VERSION 5.7 ;
  NOWIREEXTENSIONATPIN ON ;
  DIVIDERCHAR "/" ;
  BUSBITCHARS "[]" ;
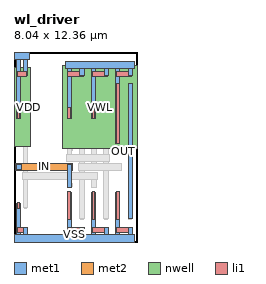
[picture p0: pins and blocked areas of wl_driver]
MACRO wl_driver
  CLASS BLOCK ;
  FOREIGN wl_driver ;
  ORIGIN 0.030 0.000 ;
  SIZE 8.040 BY 12.360 ;
  PIN IN
    DIRECTION INPUT ;
    USE SIGNAL ;
    ANTENNAGATEAREA 1.225000 ;
    PORT
      LAYER met1 ;
        RECT 0.140 4.720 0.430 5.040 ;
        RECT 3.440 3.560 3.730 5.040 ;
      LAYER met2 ;
        RECT 0.080 4.660 3.790 5.100 ;
    END
  END IN
  PIN OUT
    DIRECTION OUTPUT ;
    USE SIGNAL ;
    ANTENNADIFFAREA 1.740000 ;
    PORT
      LAYER met1 ;
        RECT 7.400 1.510 7.670 10.320 ;
    END
  END OUT
  PIN VDD
    DIRECTION INOUT ;
    USE POWER ;
    ANTENNADIFFAREA 0.552900 ;
    PORT
      LAYER nwell ;
        RECT -0.030 6.200 1.020 11.340 ;
      LAYER li1 ;
        RECT 0.190 10.790 0.800 11.120 ;
        RECT 0.190 8.030 0.360 8.720 ;
      LAYER met1 ;
        RECT 0.000 11.880 0.990 12.360 ;
        RECT 0.140 8.050 0.410 11.880 ;
        RECT 0.580 10.810 0.850 11.880 ;
    END
  END VDD
  PIN VWL
    DIRECTION INOUT ;
    USE POWER ;
    ANTENNADIFFAREA 3.068400 ;
    PORT
      LAYER nwell ;
        RECT 3.110 6.050 8.010 11.490 ;
      LAYER li1 ;
        RECT 3.480 10.790 4.480 11.120 ;
        RECT 5.060 10.790 6.060 11.120 ;
        RECT 6.640 10.790 7.640 11.120 ;
        RECT 3.480 8.030 3.650 8.720 ;
        RECT 5.060 8.030 5.230 8.720 ;
        RECT 6.640 6.410 6.810 10.340 ;
      LAYER met1 ;
        RECT 3.290 11.280 7.830 11.760 ;
        RECT 3.430 8.050 3.700 11.280 ;
        RECT 4.260 10.810 4.530 11.280 ;
        RECT 5.010 8.050 5.280 11.280 ;
        RECT 5.840 10.810 6.110 11.280 ;
        RECT 6.590 6.430 6.860 11.280 ;
        RECT 7.420 10.810 7.690 11.280 ;
    END
  END VWL
  PIN VSS
    DIRECTION INOUT ;
    USE GROUND ;
    ANTENNADIFFAREA 3.486300 ;
    PORT
      LAYER li1 ;
        RECT 0.190 2.210 0.360 2.540 ;
        RECT 3.480 1.490 3.650 3.260 ;
        RECT 5.060 1.490 5.230 3.260 ;
        RECT 6.640 1.490 6.810 3.260 ;
        RECT 0.190 0.640 0.800 0.970 ;
        RECT 3.480 0.640 4.480 0.970 ;
        RECT 5.060 0.640 6.060 0.970 ;
        RECT 6.640 0.640 7.640 0.970 ;
      LAYER met1 ;
        RECT 0.140 0.480 0.410 2.520 ;
        RECT 0.580 0.480 0.850 0.950 ;
        RECT 3.430 0.480 3.700 3.240 ;
        RECT 4.260 0.480 4.530 0.950 ;
        RECT 5.010 0.480 5.280 3.240 ;
        RECT 5.840 0.480 6.110 0.950 ;
        RECT 6.590 0.480 6.860 3.240 ;
        RECT 7.420 0.480 7.690 0.950 ;
        RECT 0.000 0.000 7.830 0.480 ;
    END
  END VSS
  OBS
      LAYER li1 ;
        RECT 0.630 8.030 0.800 8.720 ;
        RECT 4.290 8.030 4.460 8.720 ;
        RECT 5.870 8.030 6.040 8.720 ;
        RECT 3.420 5.970 3.750 6.140 ;
        RECT 5.000 5.970 5.330 6.140 ;
        RECT 6.580 4.790 6.910 4.960 ;
        RECT 5.000 3.620 5.330 3.790 ;
        RECT 0.630 2.210 0.800 2.540 ;
        RECT 4.290 1.490 4.460 3.260 ;
        RECT 5.870 1.490 6.040 3.260 ;
        RECT 0.120 4.790 0.450 4.960 ;
        RECT 3.420 3.620 3.750 3.790 ;
        RECT 7.450 6.410 7.620 10.340 ;
        RECT 7.450 1.490 7.620 3.260 ;
      LAYER met1 ;
        RECT 0.580 2.220 0.870 8.700 ;
        RECT 3.440 5.300 3.730 6.200 ;
        RECT 4.240 1.510 4.530 8.700 ;
        RECT 5.020 4.720 5.310 6.200 ;
        RECT 5.020 3.560 5.310 4.460 ;
        RECT 5.820 1.510 6.110 8.700 ;
        RECT 6.600 4.720 6.890 5.040 ;
      LAYER met2 ;
        RECT 3.380 5.240 6.170 5.680 ;
        RECT 4.180 4.660 6.950 5.100 ;
        RECT 0.520 4.080 5.370 4.520 ;
  END
END wl_driver
END LIBRARY

